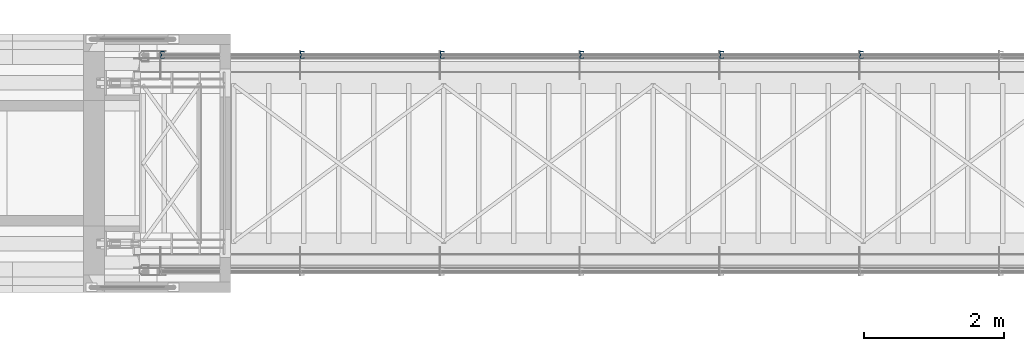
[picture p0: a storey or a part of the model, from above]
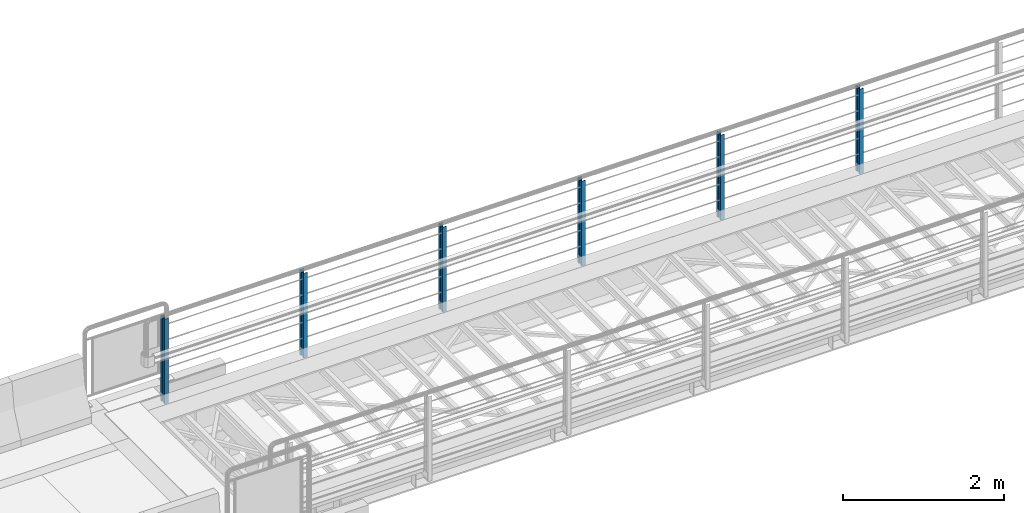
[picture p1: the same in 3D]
Properties of the parts of a building model (IFC2X3)

# File
Description: ViewDefinition[CoordinationView_V2.0, QuantityTakeOffAddOnView], ExchangeRequirement[Structural, SurfaceGeometry], Option [BaseQuantities:On], Option [GridExport:On], Option [Assemblies:Off], Option [Bolts:On], Option [Rebars:On], Option [PourObjects:Off], Option [Welds:Off], Option [SurfaceTreatments:On], Option [LocationBy:0], Option [ViewColors:Off], Option [SectionedSpine:Off], Option [PropertySets:On], Option [Export all:Off]
File name: Vippebru med betong bru.ifc
Time: 2026-04-29T15:54:14
Author: IVC\jsy
Organization: Structural Designer
Written by: IFC Parser Version: 3.13.2
Made in: Tekla Structures 2023 Service Pack 12, IFC Export Version: 4.0.0.0 Nov 4 2024

# IfcBuildingStorey, Undefined
In: Undefined
Elevation: 0 mm

# IfcBeam: CFCHS33.7*2.6 (8)
In: Undefined
Description: CFCHS33.7*2.6; Material: STEEL/S355J2+N
Pset_BeamCommon - IsExternal: no; LoadBearing: no; Reference: R-0(?)
Tekla Common - Phase: 1; Class: 3
Tekla Quantity - Volume: 0 m3; Gross footprint area: 0 m2; Area per tons: 53.2 m2; Net surface area: 0.1 m2; Height: 33.7 mm; Width: 33.7 mm
Name | Bottom elevation | Top elevation | Weight (kg) | Tekla Quantity, Length (mm) | BaseQuantities, Length (mm) | OuterSurfaceArea (m2) | NetVolume (m3) | NetWeight (kg)
4 x LKBRØYTETETTPANEL | +0.137 | +1.003 | 1.7 | 866.3 | 866.3 | 0.0918278 | 0.000210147 | 1.64965
2 x LKBRØYTETETTPANEL | +0.120 | +0.154 | 2.3 | 1175.2 | 1175.15 | 0.124566 | 0.000285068 | 2.23778
2 x LKBRØYTETETTPANEL | +0.986 | +1.020 | 2.3 | 1175.2 | 1175.15 | 0.124566 | 0.000285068 | 2.23778

# IfcBeam: CFCHS60.3*3.2 (22)
In: Undefined
Description: CFCHS60.3*3.2; Material: STEEL/S355J2+N
Pset_BeamCommon - IsExternal: no; LoadBearing: no; Reference: R-0(?)
Tekla Common - Phase: 1
Tekla Quantity - Volume: 0 m3; Gross footprint area: 0 m2; Area per tons: 41.9 m2; Height: 60.3 mm
Name | Bottom elevation | Top elevation | Class | Weight (kg) | Net surface area (m2) | Width (mm) | Tekla Quantity, Length (mm) | BaseQuantities, Length (mm) | OuterSurfaceArea (m2) | NetVolume (m3) | NetWeight (kg)
4 x LKREKKVERK | +1.094 | +1.200 | 3 | 0.5 | 0 | 3.2 | 119.4 | 119.373 | 0.0225616 | 0.0000656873 | 0.515646
4 x LKREKKVERK | +0.015 | +1.094 | 3 | 4.9 | 0.2 | 60.3 | 1078.9 | 1078.85 | 0.203903 | 0.000603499 | 4.73747
2 x LKREKKVERK | +1.140 | +1.200 | 3 | 4.6 | 0.2 | 60.3 | 1022.8 | 1022.81 | 0.193311 | 0.000572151 | 4.49139
4 x REKKVERK | +0.600 | +1.094 | 1 | 2.2 | 0.1 | 60.3 | 493.9 | 493.85 | 0.0933376 | 0.000276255 | 2.1686
4 x REKKVERK | +1.094 | +1.200 | 1 | 0.5 | 0 | 3.2 | 119.4 | 119.373 | 0.0225616 | 0.0000656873 | 0.515646
2 x BB-REKKVERK | +1.040 | +1.100 | 1 | 90.8 | 3.8 | 60.3 | 20150 | 20150 | 3.80835 | 0.0112717 | 88.4831
2 x REKKVERK | +1.140 | +1.200 | 1 | 73.3 | 3.1 | 60.3 | 16263.9 | 16263.9 | 3.07387 | 0.00909786 | 71.4182

# IfcBeam: CW100-5-10*55-10-30 (20)
In: Undefined
Description: CW100-5-10*55-10-30; Material: STEEL/S355J2+N
Tekla Common - Bottom elevation: -0.150; Phase: 1; Class: 1
Tekla Quantity - Volume: 0 m3; Gross footprint area: 0 m2; Area per tons: 52.5 m2; Height: 100 mm; Width: 55 mm
Pset_BeamCommon - IsExternal: no; LoadBearing: no; Reference: ST-0(?)
Name | Top elevation | Weight (kg) | Net surface area (m2) | Tekla Quantity, Length (mm) = BaseQuantities, Length (mm) | OuterSurfaceArea (m2) | NetVolume (m3) | NetWeight (kg)
11 x BB-STOLPE | +1.040 | 10.2 | 0.5 | 1190 | 0.533593 | 0.00129508 | 10.1664
9 x STOLPE | +1.140 | 11 | 0.6 | 1290 | 0.57825 | 0.00140391 | 11.0207

# IfcBeam: D10 (4)
In: Undefined
Description: D10; Material: STEEL/S355J2+N
Pset_BeamCommon - IsExternal: no; LoadBearing: no; Reference: R-0(?)
Tekla Common - Phase: 1; Class: 1
Tekla Quantity - Weight: 11.2 kg; Volume: 0 m3; Gross footprint area: 0 m2; Area per tons: 55.2 m2; Net surface area: 0.6 m2; Height: 10 mm; Width: 10 mm; Length: 20000 mm
BaseQuantities - Length: 20000 mm; OuterSurfaceArea: 0.612435 m2; NetVolume: 0.00141421 m3; NetWeight: 11.1016 kg
Name | Bottom elevation | Top elevation
2 x BB-REKKVERK | +0.250 | +0.260
2 x BB-REKKVERK | +0.120 | +0.130

# IfcBeam: D12 (8)
In: Undefined
Description: D12; Material: STEEL/S355J2+N
Tekla Common - Phase: 1; Class: 1
Tekla Quantity - Weight: 12.8 kg; Volume: 0 m3; Gross footprint area: 0 m2; Area per tons: 46 m2; Net surface area: 0.6 m2; Height: 12 mm; Width: 12 mm; Length: 15960 mm
Pset_BeamCommon - IsExternal: no; LoadBearing: no; Reference: R-0(?)
BaseQuantities - Length: 15960 mm; OuterSurfaceArea: 0.586536 m2; NetVolume: 0.0016251 m3; NetWeight: 12.757 kg
Name | Bottom elevation | Top elevation
2 x REKKVERK | +0.114 | +0.126
2 x REKKVERK | +0.774 | +0.786
2 x REKKVERK | +1.014 | +1.026
2 x REKKVERK | +0.354 | +0.366

# IfcBeam: D205 (2)
In: Undefined
Description: D205; Material: STEEL/S355J2+N
Tekla Common - Bottom elevation: -1.723; Top elevation: -1.517; Phase: 1; Class: 11
Tekla Quantity - Weight: 539.2 kg; Volume: 0.1 m3; Gross footprint area: 0 m2; Area per tons: 2.6 m2; Net surface area: 1.4 m2; Height: 205 mm; Width: 205 mm; Length: 2105 mm
Pset_BeamCommon - IsExternal: no; LoadBearing: no; Reference: V-0(?)
BaseQuantities - Length: 2105 mm; OuterSurfaceArea: 1.41707 m2; NetVolume: 0.0686874 m3; NetWeight: 539.196 kg

# IfcBeam: FL200*5 (2)
In: Undefined
Description: FL200*5; Material: STEEL/S355J2+N
Pset_BeamCommon - IsExternal: no; LoadBearing: no; Reference: V-0(?)
Tekla Common - Bottom elevation: -0.005; Top elevation: +0.000; Phase: 1; Class: 5
Tekla Quantity - Volume: 0 m3; Gross footprint area: 3.3 m2; Area per tons: 52.2 m2; Net surface area: 6.8 m2; Height: 200 mm; Width: 5 mm
Name | Weight (kg) | Tekla Quantity, Length (mm) = BaseQuantities, Length (mm) | OuterSurfaceArea (m2) | NetVolume (m3) | NetWeight (kg)
RIST | 129.7 | 16520.9 | 6.77556 | 0.0165209 | 129.689
RIST | 129.4 | 16480 | 6.7588 | 0.01648 | 129.368

# IfcBeam: FL50*5 (4)
In: Undefined
Description: FL50*5; Material: STEEL/S355J2+N
Pset_BeamCommon - IsExternal: no; LoadBearing: no; Reference: V-0(?)
Tekla Common - Bottom elevation: -0.055; Top elevation: -0.005; Phase: 1; Class: 3
Tekla Quantity - Weight: 32.3 kg; Volume: 0 m3; Gross footprint area: 0.1 m2; Area per tons: 56.1 m2; Net surface area: 1.8 m2; Height: 50 mm; Width: 5 mm; Length: 16480 mm
BaseQuantities - Length: 16480 mm; OuterSurfaceArea: 1.8133 m2; NetVolume: 0.00412 m3; NetWeight: 32.342 kg

# IfcBeam: HEA450 (2)
In: Undefined
Description: HEA450; Material: STEEL/S355J2+N
Pset_BeamCommon - IsExternal: no; LoadBearing: no; Reference: V-0(?)
Tekla Common - Bottom elevation: -0.440; Top elevation: +0.000; Phase: 1; Class: 11
Tekla Quantity - Weight: 2302.6 kg; Volume: 0.3 m3; Gross footprint area: 4.9 m2; Area per tons: 14.5 m2; Net surface area: 33.5 m2; Height: 440 mm; Width: 300 mm; Length: 16479.1 mm
BaseQuantities - Length: 16479.1 mm; OuterSurfaceArea: 33.1395 m2; NetVolume: 0.279172 m3; NetWeight: 2191.5 kg

# IfcBeam: IPE120 (34)
In: Undefined
Description: IPE120; Material: STEEL/S355J2+N
Pset_BeamCommon - IsExternal: no; LoadBearing: no; Reference: V-0(?)
Tekla Common - Bottom elevation: -0.165; Top elevation: -0.045; Phase: 1; Class: 11
Tekla Quantity - Weight: 23.7 kg; Volume: 0 m3; Gross footprint area: 0.1 m2; Area per tons: 45.8 m2; Net surface area: 1.1 m2; Height: 120 mm; Width: 64 mm; Length: 2288.5 mm
BaseQuantities - Length: 2288.5 mm; OuterSurfaceArea: 1.08704 m2; NetVolume: 0.0029269 m3; NetWeight: 22.9762 kg

# IfcBeam: L50*5 (14)
In: Undefined
Description: L50*5; Material: STEEL/S355J2+N
Pset_BeamCommon - IsExternal: no; LoadBearing: no; Reference: V-0(?)
Tekla Common - Bottom elevation: -0.215; Top elevation: -0.165; Phase: 1; Class: 11
Tekla Quantity - Volume: 0 m3; Area per tons: 51.5 m2; Height: 50 mm; Width: 50 mm
Name | Weight (kg) | Gross footprint area (m2) | Net surface area (m2) | Tekla Quantity, Length (mm) | BaseQuantities, Length (mm) | OuterSurfaceArea (m2) | NetVolume (m3) | NetWeight (kg)
4 x STÅLBJELKE | 5.3 | 0.1 | 0.3 | 1400 | 1400 | 0.2716 | 0.000665 | 5.22025
10 x STÅLBJELKE | 14.1 | 0.2 | 0.6 | 3744 | 3744.01 | 0.726338 | 0.0017784 | 13.9605

# IfcBeam: O120*20 (4)
In: Undefined
Description: O120*20; Material: STEEL/S355J2+N
Pset_BeamCommon - IsExternal: no; LoadBearing: no; Reference: V-0(?)
Tekla Common - Bottom elevation: -1.680; Top elevation: -1.560; Phase: 1; Class: 4
Tekla Quantity - Weight: 1.9 kg; Volume: 0 m3; Gross footprint area: 0 m2; Area per tons: 11.6 m2; Net surface area: 0 m2; Height: 120 mm; Width: 120 mm; Length: 40 mm
BaseQuantities - Length: 40 mm; OuterSurfaceArea: 0.0224341 m2; NetVolume: 0.000247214 m3; NetWeight: 1.94063 kg

# IfcBeam: O120*25 (4)
In: Undefined
Description: O120*25; Material: STEEL/S355J2+N
Tekla Common - Bottom elevation: -1.680; Top elevation: -1.560; Phase: 1; Class: 5
Tekla Quantity - Weight: 2.3 kg; Volume: 0 m3; Gross footprint area: 0 m2; Area per tons: 10.5 m2; Net surface area: 0 m2; Height: 120 mm; Width: 120 mm; Length: 40 mm
Pset_BeamCommon - IsExternal: no; LoadBearing: no; Reference: I-0(?)
BaseQuantities - Length: 40 mm; OuterSurfaceArea: 0.0242882 m2; NetVolume: 0.000293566 m3; NetWeight: 2.30449 kg

# IfcBeam: O150*30 (6)
In: Undefined
Description: O150*30; Material: STEEL/S355J2+N
Pset_BeamCommon - IsExternal: no; LoadBearing: no
Tekla Common - Bottom elevation: -0.225; Top elevation: -0.075; Phase: 1
Tekla Quantity - Volume: 0 m3; Gross footprint area: 0 m2; Net surface area: 0 m2; Height: 150 mm; Width: 150 mm
Name | Reference | Class | Weight (kg) | Area per tons (m2) | Tekla Quantity, Length (mm) = BaseQuantities, Length (mm) | OuterSurfaceArea (m2) | NetVolume (m3) | NetWeight (kg)
4 x INNFESTING | I-0(?) | 5 | 2.6 | 10.7 | 30 | 0.0280731 | 0.000335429 | 2.63312
2 x STÅLBJELKE | V-0(?) | 11 | 5.3 | 7.9 | 60 | 0.0421699 | 0.000670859 | 5.26624

# IfcColumn: CW100-5-10*55-10-30 (20)
In: Undefined
Description: CW100-5-10*55-10-30; Material: STEEL/S355J2+N
Tekla Common - Bottom elevation: -0.150; Phase: 1; Class: 1
Tekla Quantity - Volume: 0 m3; Gross footprint area: 0 m2; Area per tons: 52.5 m2; Height: 100 mm; Width: 55 mm
Pset_ColumnCommon - IsExternal: no; LoadBearing: no; Reference: ST-0(?)
Name | Top elevation | Weight (kg) | Net surface area (m2) | Tekla Quantity, Length (mm) = BaseQuantities, Length (mm) | OuterSurfaceArea (m2) | NetVolume (m3) | NetWeight (kg)
11 x BB-STOLPE | +1.040 | 10.2 | 0.5 | 1190 | 0.533593 | 0.00129508 | 10.1664
9 x STOLPE | +1.140 | 11 | 0.6 | 1290 | 0.57825 | 0.00140391 | 11.0207

# IfcPlate: PL1*830 (2)
In: Undefined
Description: PL1*830; Material: STEEL/S355J2+N
Pset_PlateCommon - IsExternal: no; LoadBearing: no; Reference: 0(?)
Tekla Common - Bottom elevation: +0.155; Top elevation: +0.985; Phase: 1; Class: 3
Tekla Quantity - Weight: 6 kg; Volume: 0 m3; Gross footprint area: 0 m2; Area per tons: 255.4 m2; Net surface area: 1.4 m2; Height: 830 mm; Width: 1 mm; Length: 920 mm
BaseQuantities - Width: 830 mm; NetArea: 1.5307 m2; GrossArea: 0.7636 m2; CrossSectionArea: 0.000001 m2; NetVolume: 0.0007636 m3; GrossVolume: 0.0007636 m3

# IfcPlate: PL10*190 (2)
In: Undefined
Description: PL10*190; Material: STEEL/S355J2+N
Pset_PlateCommon - IsExternal: no; LoadBearing: no; Reference: V-0(?)
Tekla Common - Bottom elevation: +0.000; Top elevation: +0.010; Phase: 1; Class: 5
Tekla Quantity - Weight: 11.2 kg; Volume: 0 m3; Gross footprint area: 0.1 m2; Area per tons: 27.2 m2; Net surface area: 0.3 m2; Height: 190 mm; Width: 10 mm; Length: 750 mm
BaseQuantities - Width: 190 mm; NetArea: 0.3038 m2; GrossArea: 0.1425 m2; CrossSectionArea: 0.0001 m2; NetVolume: 0.001425 m3; GrossVolume: 0.001425 m3

# IfcPlate: PL10*500, OVERGANGSPLATE
In: Undefined
Description: PL10*500; Material: STEEL/S355J2+N
Pset_PlateCommon - IsExternal: no; LoadBearing: no; Reference: V-0(?)
Tekla Common - Bottom elevation: +0.000; Top elevation: +0.010; Phase: 1; Class: 5
Tekla Quantity - Weight: 117.8 kg; Volume: 0 m3; Gross footprint area: 1.5 m2; Area per tons: 26.1 m2; Net surface area: 3.1 m2; Height: 500 mm; Width: 10 mm; Length: 3000 mm
BaseQuantities - Width: 500 mm; NetArea: 3.07 m2; GrossArea: 1.5 m2; CrossSectionArea: 0.0001 m2; NetVolume: 0.015 m3; GrossVolume: 0.015 m3

# IfcPlate: PL15*120 (4)
In: Undefined
Description: PL15*120
Pset_PlateCommon - IsExternal: no; LoadBearing: no; Reference: 0(?)
Tekla Common - Bottom elevation: +0.000; Top elevation: +0.015; Phase: 1; Class: 3
Tekla Quantity - Weight: 2.3 kg; Volume: 0 m3; Gross footprint area: 0 m2; Area per tons: 20.7 m2; Net surface area: 0 m2; Height: 120 mm; Width: 15 mm; Length: 160 mm
BaseQuantities - Width: 120 mm; NetArea: 0.0468 m2; GrossArea: 0.019201 m2; CrossSectionArea: 0.000225 m2; NetVolume: 0.000288 m3; GrossVolume: 0.000288 m3
Name | Material
2 x LKREKKVERK | STEEL/S355J2+N
2 x LKREKKVERK | STEEL/S235JR

# IfcPlate: PL155*150 (4)
In: Undefined
Description: PL155*150; Material: STEEL/S355J2+N
Tekla Common - Bottom elevation: +0.523; Top elevation: +0.678; Phase: 1; Class: 1
Tekla Quantity - Volume: 0 m3; Gross footprint area: 0 m2; Net surface area: 0.2 m2; Height: 150 mm; Width: 155 mm
Pset_PlateCommon - IsExternal: no; LoadBearing: no; Reference: 0(?)
BaseQuantities - Width: 150 mm; CrossSectionArea: 0.024025 m2
Name | Weight (kg) | Area per tons (m2) | Length (mm) | NetArea (m2) | GrossArea (m2) | NetVolume (m3) = GrossVolume (m3)
2 x FØRINGSSKINNE | 4 | 53 | 375 | 0.209772 | 0.05625 | 0.00050433
2 x FØRINGSSKINNE | 3.4 | 53.1 | 275 | 0.177772 | 0.04125 | 0.00042683

# IfcPlate: PL16270*131 (2)
In: Undefined
Description: PL16270*131; Material: STEEL/S355J2+N
Tekla Common - Bottom elevation: +0.523; Top elevation: +0.678; Phase: 1; Class: 1
Pset_PlateCommon - IsExternal: no; LoadBearing: no; Reference: R-0(?)
Tekla Quantity - Weight: 90.4 kg; Volume: 0 m3; Gross footprint area: 0 m2; Area per tons: 88.3 m2; Net surface area: 8 m2; Height: 131.4 mm; Width: 16270 mm; Length: 102.7 mm
BaseQuantities - Width: 131.445 mm; NetArea: 7.98874 m2; GrossArea: 0.0134987 m2; CrossSectionArea: 264.713 m2; NetVolume: 0.0115183 m3; GrossVolume: 0.0115183 m3

# IfcPlate: PL18*144 (4)
In: Undefined
Description: PL18*144; Material: STEEL/S355J2+N
Pset_PlateCommon - IsExternal: no; LoadBearing: no; Reference: V-0(?)
Tekla Common - Bottom elevation: -0.419; Top elevation: -0.021; Phase: 1; Class: 4
Tekla Quantity - Weight: 8.1 kg; Volume: 0 m3; Gross footprint area: 0 m2; Area per tons: 16.6 m2; Net surface area: 0.1 m2; Height: 144.3 mm; Width: 18 mm; Length: 398 mm
BaseQuantities - Width: 144.25 mm; NetArea: 0.134344 m2; GrossArea: 0.0574115 m2; CrossSectionArea: 0.000324 m2; NetVolume: 0.00103341 m3; GrossVolume: 0.00103341 m3

# IfcPlate: PL18*239 (2)
In: Undefined
Description: PL18*239; Material: STEEL/S355J2+N
Pset_PlateCommon - IsExternal: no; LoadBearing: no; Reference: V-0(?)
Tekla Common - Bottom elevation: -0.422; Top elevation: -0.183; Phase: 1; Class: 4
Tekla Quantity - Weight: 77.3 kg; Volume: 0 m3; Gross footprint area: 0 m2; Area per tons: 15.2 m2; Net surface area: 1.2 m2; Height: 239 mm; Width: 18 mm; Length: 2288.5 mm
BaseQuantities - Width: 239 mm; NetArea: 1.18489 m2; GrossArea: 0.546952 m2; CrossSectionArea: 0.000324 m2; NetVolume: 0.00984513 m3; GrossVolume: 0.00984513 m3

# IfcPlate: PL18*370 (2)
In: Undefined
Description: PL18*370; Material: STEEL/S355J2+N
Pset_PlateCommon - IsExternal: no; LoadBearing: no; Reference: V-0(?)
Tekla Common - Phase: 1; Class: 4
Tekla Quantity - Weight: 119.6 kg; Volume: 0 m3; Gross footprint area: 0.7 m2; Area per tons: 15 m2; Net surface area: 1.8 m2; Height: 370 mm; Width: 18 mm; Length: 2288.5 mm
BaseQuantities - Width: 370 mm; NetArea: 1.7892 m2; GrossArea: 0.846745 m2; CrossSectionArea: 0.000324 m2; NetVolume: 0.0152414 m3; GrossVolume: 0.0152414 m3
Name | Bottom elevation | Top elevation
PLATE | -0.183 | -0.165
PLATE | -0.440 | -0.422

# IfcPlate: PL18*466 (4)
In: Undefined
Description: PL18*466; Material: STEEL/S355J2+N
Pset_PlateCommon - IsExternal: no; LoadBearing: no; Reference: V-0(?)
Tekla Common - Bottom elevation: -1.736; Top elevation: -0.440; Phase: 1; Class: 4
Tekla Quantity - Weight: 90.7 kg; Volume: 0 m3; Gross footprint area: 0 m2; Area per tons: 15.2 m2; Net surface area: 1.4 m2; Height: 466.4 mm; Width: 18 mm; Length: 2201.5 mm
BaseQuantities - Width: 466.39 mm; NetArea: 1.37477 m2; GrossArea: 1.02674 m2; CrossSectionArea: 0.000324 m2; NetVolume: 0.0115507 m3; GrossVolume: 0.011751 m3

# IfcPlate: PL20*144 (8)
In: Undefined
Description: PL20*144; Material: STEEL/S355J2+N
Pset_PlateCommon - IsExternal: no; LoadBearing: no; Reference: V-0(?)
Tekla Common - Bottom elevation: -0.419; Top elevation: -0.021; Phase: 1; Class: 4
Tekla Quantity - Weight: 9 kg; Volume: 0 m3; Gross footprint area: 0 m2; Area per tons: 15.2 m2; Net surface area: 0.1 m2; Height: 144.3 mm; Width: 20 mm; Length: 398 mm
BaseQuantities - Width: 144.25 mm; NetArea: 0.136513 m2; GrossArea: 0.0574115 m2; CrossSectionArea: 0.0004 m2; NetVolume: 0.00114823 m3; GrossVolume: 0.00114823 m3

# IfcPlate: PL20*230 (2)
In: Undefined
Description: PL20*230; Material: STEEL/S355J2+N
Pset_PlateCommon - IsExternal: no; LoadBearing: no; Reference: I-0(?)
Tekla Common - Bottom elevation: -0.380; Top elevation: -0.150; Phase: 1; Class: 5
Tekla Quantity - Weight: 12.6 kg; Volume: 0 m3; Gross footprint area: 0 m2; Area per tons: 14.6 m2; Net surface area: 0.2 m2; Height: 230 mm; Width: 20 mm; Length: 350 mm
BaseQuantities - Width: 230 mm; NetArea: 0.1842 m2; GrossArea: 0.0805 m2; CrossSectionArea: 0.0004 m2; NetVolume: 0.00161 m3; GrossVolume: 0.00161 m3

# IfcPlate: PL20*270 (4)
In: Undefined
Description: PL20*270; Material: STEEL/S355J2+N
Tekla Common - Bottom elevation: -1.830; Top elevation: -1.560; Phase: 1; Class: 5
Tekla Quantity - Weight: 12.5 kg; Volume: 0 m3; Gross footprint area: 0 m2; Area per tons: 15 m2; Net surface area: 0.2 m2; Height: 270.3 mm; Width: 20 mm; Length: 340.2 mm
Pset_PlateCommon - IsExternal: no; LoadBearing: no; Reference: I-0(?)
BaseQuantities - Width: 270.31 mm; NetArea: 0.18825 m2; GrossArea: 0.0919571 m2; CrossSectionArea: 0.0004 m2; NetVolume: 0.00159834 m3; GrossVolume: 0.00182013 m3

# IfcPlate: PL20*300 (10)
In: Undefined
Description: PL20*300; Material: STEEL/S355J2+N
Tekla Common - Phase: 1
Tekla Quantity - Volume: 0 m3; Gross footprint area: 0 m2; Height: 300 mm; Width: 20 mm
Pset_PlateCommon - IsExternal: no; LoadBearing: no
BaseQuantities - CrossSectionArea: 0.0004 m2
Name | Bottom elevation | Top elevation | Class | Weight (kg) | Area per tons (m2) | Net surface area (m2) | Length (mm) | Reference | Width (mm) | NetArea (m2) | GrossArea (m2) | NetVolume (m3) | GrossVolume (m3)
2 x PLATE | -0.317 | -0.021 | 4 | 14.4 | 14.5 | 0.2 | 315.3 | V-0(?) | 300 | 0.209355 | 0.0945777 | 0.0018391 | 0.002028
2 x PLATE | -0.440 | -0.316 | 4 | 21.4 | 14.2 | 0.3 | 457.2 | V-0(?) | 300 | 0.303273 | 0.137163 | 0.00272915 | 0.002748
2 x INNFESTING | -1.830 | -1.530 | 5 | 16.5 | 14.2 | 0.2 | 350 | I-0(?) | 300 | 0.236 | 0.105 | 0.0021 | 0.0021
PLATE | -1.518 | -0.440 | 4 | 68.4 | 13.8 | 0.9 | 1461.5 | V-0(?) | 300.006 | 0.943633 | 0.438464 | 0.0087138 | 0.00881991
2 x PLATE | -1.666 | -0.440 | 4 | 94.8 | 13.8 | 1.2 | 2024.9 | V-0(?) | 300 | 1.30345 | 0.607476 | 0.0120707 | 0.0121495
PLATE | -1.518 | -0.440 | 4 | 68 | 13.8 | 0.9 | 1443.4 | V-0(?) | 300.006 | 0.935742 | 0.433017 | 0.00866009 | 0.00866009

# IfcPlate: PL20*350 (4)
In: Undefined
Description: PL20*350; Material: STEEL/S355J2+N
Pset_PlateCommon - IsExternal: no; LoadBearing: no; Reference: I-0(?)
Tekla Common - Phase: 1; Class: 5
Tekla Quantity - Weight: 27.5 kg; Volume: 0 m3; Gross footprint area: 0.2 m2; Area per tons: 14 m2; Net surface area: 0.3 m2; Height: 350 mm; Width: 20 mm; Length: 500 mm
BaseQuantities - Width: 350 mm; NetArea: 0.384 m2; GrossArea: 0.175 m2; CrossSectionArea: 0.0004 m2; NetVolume: 0.0035 m3; GrossVolume: 0.0035 m3
Name | Bottom elevation | Top elevation
2 x INNFESTING | -1.850 | -1.830
2 x INNFESTING | -0.400 | -0.380

# IfcPlate: PL20*355 (4)
In: Undefined
Description: PL20*355; Material: STEEL/S355J2+N
Pset_PlateCommon - IsExternal: no; LoadBearing: no; Reference: I-0(?)
Tekla Common - Bottom elevation: -0.380; Top elevation: -0.025; Phase: 1; Class: 5
Tekla Quantity - Weight: 18.2 kg; Volume: 0 m3; Gross footprint area: 0 m2; Area per tons: 15 m2; Net surface area: 0.3 m2; Height: 354.8 mm; Width: 20 mm; Length: 480 mm
BaseQuantities - Width: 354.777 mm; NetArea: 0.270588 m2; GrossArea: 0.170293 m2; CrossSectionArea: 0.0004 m2; NetVolume: 0.0023211 m3; GrossVolume: 0.0026705 m3

# IfcPlate: PL20100*131 (2)
In: Undefined
Description: PL20100*131; Material: STEEL/S355J2+N
Tekla Common - Bottom elevation: +0.523; Top elevation: +0.678; Phase: 1; Class: 1
Tekla Quantity - Weight: 111.7 kg; Volume: 0 m3; Gross footprint area: 0 m2; Area per tons: 88.3 m2; Net surface area: 9.9 m2; Height: 131.4 mm; Width: 20100 mm; Length: 102.7 mm
Pset_PlateCommon - IsExternal: no; LoadBearing: no; Reference: R-0(?)
BaseQuantities - Width: 131.445 mm; NetArea: 9.86897 m2; GrossArea: 0.0134987 m2; CrossSectionArea: 404.01 m2; NetVolume: 0.0142298 m3; GrossVolume: 0.0142298 m3

# IfcPlate: PL40*291 (2)
In: Undefined
Description: PL40*291; Material: STEEL/S355J2+N
Pset_PlateCommon - IsExternal: no; LoadBearing: no; Reference: I-0(?)
Tekla Common - Bottom elevation: -0.312; Top elevation: -0.021; Phase: 1; Class: 11
Tekla Quantity - Weight: 26.2 kg; Volume: 0 m3; Gross footprint area: 0 m2; Area per tons: 8.2 m2; Net surface area: 0.2 m2; Height: 291 mm; Width: 40 mm; Length: 393.4 mm
BaseQuantities - Width: 291.008 mm; NetArea: 0.215701 m2; GrossArea: 0.114473 m2; CrossSectionArea: 0.0016 m2; NetVolume: 0.00334393 m3; GrossVolume: 0.00334393 m3

# IfcPlate: PL45*2000, RIST
In: Undefined
Description: PL45*2000; Material: STEEL/S355J2+N
Pset_PlateCommon - IsExternal: no; LoadBearing: no; Reference: I-0(?)
Tekla Common - Bottom elevation: -0.045; Top elevation: +0.000; Phase: 1; Class: 5
Tekla Quantity - Weight: 11643.1 kg; Volume: 1.5 m3; Gross footprint area: 33 m2; Area per tons: 5.8 m2; Net surface area: 67.6 m2; Height: 2000 mm; Width: 45 mm; Length: 16480 mm
BaseQuantities - Width: 2000 mm; NetArea: 67.5832 m2; GrossArea: 32.96 m2; CrossSectionArea: 0.002025 m2; NetVolume: 1.4832 m3; GrossVolume: 1.4832 m3

# IfcPlate: PL5*362, PLATE
In: Undefined
Description: PL5*362; Material: STEEL/S355J2+N
Pset_PlateCommon - IsExternal: no; LoadBearing: no; Reference: V-0(?)
Tekla Common - Bottom elevation: -0.383; Top elevation: -0.021; Phase: 1; Class: 4
Tekla Quantity - Weight: 2.6 kg; Volume: 0 m3; Gross footprint area: 0 m2; Area per tons: 53.9 m2; Net surface area: 0.1 m2; Height: 362 mm; Width: 5 mm; Length: 400 mm
BaseQuantities - Width: 362 mm; NetArea: 0.14002 m2; GrossArea: 0.1448 m2; CrossSectionArea: 0.000025 m2; NetVolume: 0.000331 m3; GrossVolume: 0.000331 m3

# IfcPlate: PL5*363, PLATE
In: Undefined
Description: PL5*363; Material: STEEL/S355J2+N
Pset_PlateCommon - IsExternal: no; LoadBearing: no; Reference: V-0(?)
Tekla Common - Bottom elevation: -0.384; Top elevation: -0.021; Phase: 1; Class: 4
Tekla Quantity - Weight: 2.6 kg; Volume: 0 m3; Gross footprint area: 0 m2; Area per tons: 53.9 m2; Net surface area: 0.1 m2; Height: 363.2 mm; Width: 5 mm; Length: 400 mm
BaseQuantities - Width: 363.153 mm; NetArea: 0.140152 m2; GrossArea: 0.145261 m2; CrossSectionArea: 0.000025 m2; NetVolume: 0.000331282 m3; GrossVolume: 0.000349 m3

# IfcPlate: PL5*398 (16)
In: Undefined
Description: PL5*398; Material: STEEL/S355J2+N
Pset_PlateCommon - IsExternal: no; LoadBearing: no; Reference: V-0(?)
Tekla Common - Bottom elevation: -0.419; Top elevation: -0.021; Phase: 1; Class: 4
Tekla Quantity - Weight: 2.7 kg; Volume: 0 m3; Gross footprint area: 0 m2; Area per tons: 53.9 m2; Net surface area: 0.1 m2; Height: 398 mm; Width: 5 mm; Length: 400 mm
BaseQuantities - Width: 398 mm; NetArea: 0.14758 m2; GrossArea: 0.1592 m2; CrossSectionArea: 0.000025 m2; NetVolume: 0.000349 m3; GrossVolume: 0.000349 m3

# IfcPlate: PL50*1200, LUKE
In: Undefined
Description: PL50*1200; Material: STEEL/S355J2+N
Pset_PlateCommon - IsExternal: no; LoadBearing: no; Reference: V-0(?)
Tekla Common - Bottom elevation: -0.050; Top elevation: +0.000; Phase: 1; Class: 4
Tekla Quantity - Weight: 706.5 kg; Volume: 0.1 m3; Gross footprint area: 1.7 m2; Area per tons: 5.5 m2; Net surface area: 3.9 m2; Height: 1200 mm; Width: 50 mm; Length: 1500 mm
BaseQuantities - Width: 1200 mm; NetArea: 3.87 m2; GrossArea: 1.8 m2; CrossSectionArea: 0.0025 m2; NetVolume: 0.09 m3; GrossVolume: 0.09 m3

# IfcPlate: PL50*700 (2)
In: Undefined
Description: PL50*700; Material: STEEL/S355J2+N
Pset_PlateCommon - IsExternal: no; LoadBearing: no; Reference: V-0(?)
Tekla Common - Bottom elevation: -0.050; Top elevation: +0.000; Phase: 1; Class: 4
Tekla Quantity - Weight: 631.9 kg; Volume: 0.1 m3; Gross footprint area: 1.6 m2; Area per tons: 5.6 m2; Net surface area: 3.5 m2; Height: 700 mm; Width: 50 mm; Length: 2300 mm
BaseQuantities - Width: 700 mm; NetArea: 3.52 m2; GrossArea: 1.61 m2; CrossSectionArea: 0.0025 m2; NetVolume: 0.0805 m3; GrossVolume: 0.0805 m3

# IfcPlate: PL74*177 (2)
In: Undefined
Description: PL74*177; Material: STEEL/S355J2+N
Pset_PlateCommon - IsExternal: no; LoadBearing: no; Reference: V-0(?)
Tekla Common - Bottom elevation: -1.722; Top elevation: -1.517; Phase: 1; Class: 11
Tekla Quantity - Weight: 15.5 kg; Volume: 0 m3; Gross footprint area: 0 m2; Area per tons: 7.9 m2; Net surface area: 0.1 m2; Height: 177 mm; Width: 74 mm; Length: 205 mm
BaseQuantities - Width: 177 mm; NetArea: 0.121902 m2; GrossArea: 0.036285 m2; CrossSectionArea: 0.005476 m2; NetVolume: 0.00197536 m3; GrossVolume: 0.00233783 m3

# IfcPlate: PL74*205 (2)
In: Undefined
Description: PL74*205; Material: STEEL/S355J2+N
Pset_PlateCommon - IsExternal: no; LoadBearing: no; Reference: V-0(?)
Tekla Common - Bottom elevation: -1.722; Top elevation: -1.517; Phase: 1; Class: 11
Tekla Quantity - Weight: 20.4 kg; Volume: 0 m3; Gross footprint area: 0 m2; Area per tons: 7.1 m2; Net surface area: 0.1 m2; Height: 205 mm; Width: 74 mm; Length: 218 mm
BaseQuantities - Width: 205 mm; NetArea: 0.14478 m2; GrossArea: 0.04469 m2; CrossSectionArea: 0.005476 m2; NetVolume: 0.00259733 m3; GrossVolume: 0.0029598 m3

# IfcSlab: 1020*860 (2)
In: Undefined
Description: 1020*860; Material: CONCRETE/B35
Tekla Common - Bottom elevation: -0.000; Top elevation: +0.860; Phase: 1; Class: 1
Pset_SlabCommon - IsExternal: no; Compartmentation: no; LoadBearing: no; Reference: CP_PD-1-0(?)
Tekla Quantity - Weight: 572.8 kg; Volume: 0.2 m3; Gross footprint area: 0.1 m2; Area per tons: 5 m2; Net surface area: 2.8 m2; Height: 860 mm; Width: 1020 mm; Length: 440 mm
BaseQuantities - Width: 1020 mm; NetVolume: 0.23868 m3; NetArea: 0.1224 m2; NetWeight: 572.833 kg

# IfcSlab: 120*3700, PLASSTØPTDEKKE
In: Undefined
Description: 120*3700; Material: CONCRETE/B35
Pset_SlabCommon - IsExternal: no; Compartmentation: no; LoadBearing: no; Reference: CP_PD-1-0(?)
Tekla Common - Bottom elevation: -0.120; Top elevation: +0.000; Phase: 1; Class: 1
Tekla Quantity - Weight: 21471.8 kg; Volume: 8.9 m3; Gross footprint area: 74.6 m2; Area per tons: 7.1 m2; Net surface area: 154.8 m2; Height: 3700 mm; Width: 120 mm; Length: 20150 mm
BaseQuantities - Width: 120 mm; NetVolume: 8.9466 m3; NetArea: 74.555 m2; NetWeight: 21471.8 kg

# IfcSlab: 1360*860 (6)
In: Undefined
Description: 1360*860; Material: CONCRETE/B35
Tekla Common - Bottom elevation: -0.000; Top elevation: +0.860; Phase: 1; Class: 1
Tekla Quantity - Weight: 763.8 kg; Volume: 0.3 m3; Gross footprint area: 0.2 m2; Area per tons: 4.8 m2; Net surface area: 3.6 m2; Height: 860 mm; Width: 1360 mm; Length: 440 mm
Pset_SlabCommon - IsExternal: no; Compartmentation: no; LoadBearing: no; Reference: CP_PD-1-0(?)
BaseQuantities - Width: 1360 mm; NetVolume: 0.31824 m3; NetArea: 0.1632 m2; NetWeight: 763.777 kg

# IfcSlab: 200*1100, PLASSTØPTDEKKE
In: Undefined
Description: 200*1100; Material: CONCRETE/B35
Pset_SlabCommon - IsExternal: no; Compartmentation: no; LoadBearing: no; Reference: CP_PD-1-0(?)
Tekla Common - Bottom elevation: -0.200; Top elevation: +0.000; Phase: 1; Class: 1
Tekla Quantity - Weight: 792 kg; Volume: 0.3 m3; Gross footprint area: 1.7 m2; Area per tons: 5.5 m2; Net surface area: 4.3 m2; Height: 1100 mm; Width: 200 mm; Length: 1500 mm
BaseQuantities - Width: 200 mm; NetVolume: 0.33 m3; NetArea: 1.65 m2; NetWeight: 792 kg

# IfcSlab: 200*2500, PLASSTØPTDEKKE
In: Undefined
Description: 200*2500; Material: CONCRETE/B35
Pset_SlabCommon - IsExternal: no; Compartmentation: no; LoadBearing: no; Reference: CP_PD-1-0(?)
Tekla Common - Bottom elevation: -0.200; Top elevation: +0.000; Phase: 1; Class: 1
Tekla Quantity - Weight: 3840 kg; Volume: 1.6 m3; Gross footprint area: 8 m2; Area per tons: 4.8 m2; Net surface area: 18.3 m2; Height: 2500 mm; Width: 200 mm; Length: 3200 mm
BaseQuantities - Width: 200 mm; NetVolume: 1.6 m3; NetArea: 8 m2; NetWeight: 3840 kg

# IfcSlab: 250*3700, PLASSTØPTDEKKE
In: Undefined
Description: 250*3700; Material: CONCRETE/B35
Pset_SlabCommon - IsExternal: no; Compartmentation: no; LoadBearing: no; Reference: CP_PD-1-0(?)
Tekla Common - Bottom elevation: -2.100; Top elevation: -1.850; Phase: 1; Class: 1
Tekla Quantity - Weight: 15984 kg; Volume: 6.7 m3; Gross footprint area: 26.6 m2; Area per tons: 3.7 m2; Net surface area: 58.7 m2; Height: 3700 mm; Width: 250 mm; Length: 7200 mm
BaseQuantities - Width: 250 mm; NetVolume: 6.66 m3; NetArea: 26.64 m2; NetWeight: 15984 kg

# IfcSlab: 250*750, PLASSTØPTDEKKE
In: Undefined
Description: 250*750; Material: CONCRETE/B35
Pset_SlabCommon - IsExternal: no; Compartmentation: no; LoadBearing: no; Reference: CP_PD-1-0(?)
Tekla Common - Bottom elevation: -2.350; Top elevation: -2.100; Phase: 1; Class: 1
Tekla Quantity - Weight: 1665 kg; Volume: 0.8 m3; Gross footprint area: 2.8 m2; Area per tons: 4.7 m2; Net surface area: 7.8 m2; Height: 750 mm; Width: 250 mm; Length: 3700 mm
BaseQuantities - Width: 250 mm; NetVolume: 0.69375 m3; NetArea: 2.775 m2; NetWeight: 1665 kg

# IfcSlab: 800*3700, PLASSTØPTDEKKE
In: Undefined
Description: 800*3700; Material: CONCRETE/B35
Pset_SlabCommon - IsExternal: no; Compartmentation: no; LoadBearing: no; Reference: CP_PD-1-0(?)
Tekla Common - Bottom elevation: -0.920; Top elevation: -0.120; Phase: 1; Class: 1
Tekla Quantity - Weight: 142080 kg; Volume: 59.2 m3; Gross footprint area: 74 m2; Area per tons: 1.3 m2; Net surface area: 185.9 m2; Height: 3700 mm; Width: 800 mm; Length: 20000 mm
BaseQuantities - Width: 800 mm; NetVolume: 59.2 m3; NetArea: 74 m2; NetWeight: 142080 kg

# IfcWall: 1200*250 (2)
In: Undefined
Description: 1200*250; Material: CONCRETE/B35
Pset_WallCommon - IsExternal: no; Compartmentation: no; LoadBearing: no; Reference: CP_PV-1-0(?)
Tekla Common - Bottom elevation: -3.300; Top elevation: -2.100; Phase: 1; Class: 1
Tekla Quantity - Weight: 2016 kg; Volume: 0.8 m3; Gross footprint area: 0.7 m2; Area per tons: 4.3 m2; Net surface area: 8.7 m2; Height: 1200 mm; Width: 250 mm; Length: 2800 mm
BaseQuantities - Length: 2800 mm; OuterSurfaceArea: 8.72 m2; NetVolume: 0.84 m3; NetWeight: 2016 kg

# IfcWall: 1200*300, PLASSTØPTVEGG
In: Undefined
Description: 1200*300; Material: CONCRETE/B35
Pset_WallCommon - IsExternal: no; Compartmentation: no; LoadBearing: no; Reference: CP_PV-1-0(?)
Tekla Common - Bottom elevation: -3.300; Top elevation: -2.100; Phase: 1; Class: 1
Tekla Quantity - Weight: 2764.8 kg; Volume: 1.2 m3; Gross footprint area: 1 m2; Area per tons: 3.7 m2; Net surface area: 10.3 m2; Height: 1200 mm; Width: 300 mm; Length: 3200 mm
BaseQuantities - Length: 3200 mm; OuterSurfaceArea: 10.32 m2; NetVolume: 1.152 m3; NetWeight: 2764.8 kg

# IfcWall: 1300*150 (3)
In: Undefined
Description: 1300*150; Material: CONCRETE/B35
Pset_WallCommon - IsExternal: no; Compartmentation: no; LoadBearing: no; Reference: CP_PV-1-0(?)
Tekla Common - Bottom elevation: -1.850; Top elevation: -0.550; Phase: 1; Class: 1
Tekla Quantity - Height: 1300 mm; Width: 150 mm
Name | Weight (kg) = NetWeight (kg) | Volume (m3) | Gross footprint area (m2) | Area per tons (m2) | Net surface area (m2) | Tekla Quantity, Length (mm) = BaseQuantities, Length (mm) | OuterSurfaceArea (m2) | NetVolume (m3)
PLASSTØPTVEGG | 889.2 | 0.3 | 0.4 | 6.6 | 5.9 | 1900 | 5.9 | 0.3705
2 x PLASSTØPTVEGG | 163.8 | 0.1 | 0.1 | 8.6 | 1.4 | 350 | 1.405 | 0.06825

# IfcWall: 1850*150 (4)
In: Undefined
Description: 1850*150; Material: CONCRETE/B35
Pset_WallCommon - IsExternal: no; Compartmentation: no; LoadBearing: no; Reference: CP_PV-1-0(?)
Tekla Common - Bottom elevation: -1.850; Top elevation: +0.000; Phase: 1; Class: 1
Tekla Quantity - Gross footprint area: 0.4 m2; Height: 1850 mm; Width: 150 mm
Name | Weight (kg) = NetWeight (kg) | Volume (m3) | Area per tons (m2) | Net surface area (m2) | Tekla Quantity, Length (mm) = BaseQuantities, Length (mm) | OuterSurfaceArea (m2) | NetVolume (m3)
2 x PLASSTØPTVEGG | 1531.8 | 0.6 | 6.3 | 9.9 | 2300 | 9.755 | 0.63825
2 x PLASSTØPTVEGG | 1198.8 | 0.5 | 6.5 | 7.8 | 1800 | 7.755 | 0.4995

# IfcWall: 1850*250 (4)
In: Undefined
Description: 1850*250; Material: CONCRETE/B35
Pset_WallCommon - IsExternal: no; Compartmentation: no; LoadBearing: no; Reference: CP_PV-1-0(?)
Tekla Common - Bottom elevation: -1.850; Top elevation: +0.000; Phase: 1; Class: 1
Tekla Quantity - Volume: 1.2 m3; Gross footprint area: 0.7 m2; Area per tons: 4.1 m2; Height: 1850 mm; Width: 250 mm
Name | Weight (kg) = NetWeight (kg) | Net surface area (m2) | Tekla Quantity, Length (mm) = BaseQuantities, Length (mm) | OuterSurfaceArea (m2) | NetVolume (m3)
2 x PLASSTØPTVEGG | 2886 | 11.8 | 2600 | 11.845 | 1.2025
2 x PLASSTØPTVEGG | 3108 | 12.7 | 2800 | 12.685 | 1.295

# IfcWall: 1850*300 (2)
In: Undefined
Description: 1850*300; Material: CONCRETE/B35
Pset_WallCommon - IsExternal: no; Compartmentation: no; LoadBearing: no; Reference: CP_PV-1-0(?)
Tekla Common - Bottom elevation: -1.850; Top elevation: +0.000; Phase: 1; Class: 1
Tekla Quantity - Height: 1850 mm; Width: 300 mm
Name | Weight (kg) = NetWeight (kg) | Volume (m3) | Gross footprint area (m2) | Area per tons (m2) | Net surface area (m2) | Tekla Quantity, Length (mm) = BaseQuantities, Length (mm) | OuterSurfaceArea (m2) | NetVolume (m3)
PLASSTØPTVEGG | 2397.6 | 1 | 0.4 | 3.7 | 8.9 | 1800 | 8.85 | 0.999
PLASSTØPTVEGG | 4262.4 | 1.8 | 1 | 3.5 | 14.9 | 3200 | 14.87 | 1.776

# IfcWall: 380*3700, PLASSTØPTVEGG
In: Undefined
Description: 380*3700; Material: CONCRETE/B35
Pset_WallCommon - IsExternal: no; Compartmentation: no; LoadBearing: no; Reference: CP_PV-1-0(?)
Tekla Common - Bottom elevation: -0.500; Top elevation: -0.120; Phase: 1; Class: 1
Tekla Quantity - Weight: 506.2 kg; Volume: 0.2 m3; Gross footprint area: 0.7 m2; Area per tons: 7.9 m2; Net surface area: 3.9 m2; Height: 380 mm; Width: 3700 mm; Length: 150 mm
BaseQuantities - Length: 150 mm; OuterSurfaceArea: 4.036 m2; NetVolume: 0.2109 m3; NetWeight: 506.16 kg

# IfcWall: 425*3700, PLASSTØPTVEGG
In: Undefined
Description: 425*3700; Material: CONCRETE/B35
Pset_WallCommon - IsExternal: no; Compartmentation: no; LoadBearing: no; Reference: CP_PV-1-0(?)
Tekla Common - Bottom elevation: -0.920; Top elevation: -0.495; Phase: 1; Class: 1
Tekla Quantity - Weight: 1132.2 kg; Volume: 0.5 m3; Gross footprint area: 1.1 m2; Area per tons: 5 m2; Net surface area: 5.6 m2; Height: 425 mm; Width: 3700 mm; Length: 300 mm
BaseQuantities - Length: 300 mm; OuterSurfaceArea: 5.62 m2; NetVolume: 0.47175 m3; NetWeight: 1132.2 kg

# IfcWall: 500*950 (2)
In: Undefined
Description: 500*950; Material: CONCRETE/B35
Pset_WallCommon - IsExternal: no; Compartmentation: no; LoadBearing: no; Reference: CP_PV-1-0(?)
Tekla Common - Bottom elevation: -0.900; Top elevation: -0.400; Phase: 1; Class: 1
Tekla Quantity - Weight: 570 kg; Volume: 0.2 m3; Gross footprint area: 0.4 m2; Area per tons: 4.3 m2; Net surface area: 2.4 m2; Height: 500 mm; Width: 950 mm; Length: 500 mm
BaseQuantities - Length: 500 mm; OuterSurfaceArea: 2.4 m2; NetVolume: 0.2375 m3; NetWeight: 570 kg

# IfcWall: 700*150 (2)
In: Undefined
Description: 700*150; Material: CONCRETE/B35
Pset_WallCommon - IsExternal: no; Compartmentation: no; LoadBearing: no; Reference: CP_PV-1-0(?)
Tekla Common - Bottom elevation: -1.850; Top elevation: -1.150; Phase: 1; Class: 1
Tekla Quantity - Weight: 100.8 kg; Volume: 0 m3; Gross footprint area: 0.1 m2; Area per tons: 8.8 m2; Net surface area: 0.9 m2; Height: 700 mm; Width: 150 mm; Length: 400 mm
BaseQuantities - Length: 400 mm; OuterSurfaceArea: 0.89 m2; NetVolume: 0.042 m3; NetWeight: 100.8 kg

# IfcWall: 750*4100, PLASSTØPTVEGG
In: Undefined
Description: 750*4100; Material: CONCRETE/B35
Pset_WallCommon - IsExternal: no; Compartmentation: no; LoadBearing: no; Reference: CP_PV-1-0(?)
Tekla Common - Bottom elevation: -1.670; Top elevation: -0.920; Phase: 1; Class: 1
Tekla Quantity - Weight: 5535 kg; Volume: 2.3 m3; Gross footprint area: 3.1 m2; Area per tons: 2.4 m2; Net surface area: 13.4 m2; Height: 750 mm; Width: 4100 mm; Length: 750 mm
BaseQuantities - Length: 750 mm; OuterSurfaceArea: 13.425 m2; NetVolume: 2.30625 m3; NetWeight: 5535 kg

# IfcWall: 800*200 (2)
In: Undefined
Description: 800*200; Material: CONCRETE/B35
Pset_WallCommon - IsExternal: no; Compartmentation: no; LoadBearing: no; Reference: CP_PV-1-0(?)
Tekla Common - Bottom elevation: -0.921; Top elevation: -0.121; Phase: 1; Class: 1
Tekla Quantity - Weight: 288 kg; Volume: 0.1 m3; Gross footprint area: 0.2 m2; Area per tons: 6.3 m2; Net surface area: 1.8 m2; Height: 800 mm; Width: 200 mm; Length: 750 mm
BaseQuantities - Length: 750 mm; OuterSurfaceArea: 1.82 m2; NetVolume: 0.12 m3; NetWeight: 288 kg

# IfcWall: 900*300 (2)
In: Undefined
Description: 900*300; Material: CONCRETE/B35
Pset_WallCommon - IsExternal: no; Compartmentation: no; LoadBearing: no; Reference: CP_PV-1-0(?)
Tekla Common - Bottom elevation: -0.900; Top elevation: +0.000; Phase: 1; Class: 1
Tekla Quantity - Weight: 453.6 kg; Volume: 0.2 m3; Gross footprint area: 0.2 m2; Area per tons: 4.8 m2; Net surface area: 2.2 m2; Height: 900 mm; Width: 300 mm; Length: 700 mm
BaseQuantities - Length: 700 mm; OuterSurfaceArea: 2.22 m2; NetVolume: 0.189 m3; NetWeight: 453.6 kg

# IfcWall: 950*100 (2)
In: Undefined
Description: 950*100; Material: CONCRETE/B35
Pset_WallCommon - IsExternal: no; Compartmentation: no; LoadBearing: no; Reference: CP_PV-1-0(?)
Tekla Common - Bottom elevation: -1.850; Top elevation: -0.900; Phase: 1; Class: 1
Tekla Quantity - Weight: 114 kg; Volume: 0 m3; Gross footprint area: 0.1 m2; Area per tons: 10.9 m2; Net surface area: 1.2 m2; Height: 950 mm; Width: 100 mm; Length: 500 mm
BaseQuantities - Length: 500 mm; OuterSurfaceArea: 1.24 m2; NetVolume: 0.0475 m3; NetWeight: 114 kg

# IfcWall: 950*150 (2)
In: Undefined
Description: 950*150; Material: CONCRETE/B35
Pset_WallCommon - IsExternal: no; Compartmentation: no; LoadBearing: no; Reference: CP_PV-1-0(?)
Tekla Common - Bottom elevation: -1.850; Top elevation: -0.900; Phase: 1; Class: 1
Tekla Quantity - Weight: 171 kg; Volume: 0.1 m3; Gross footprint area: 0.1 m2; Area per tons: 8.1 m2; Net surface area: 1.4 m2; Height: 950 mm; Width: 150 mm; Length: 500 mm
BaseQuantities - Length: 500 mm; OuterSurfaceArea: 1.385 m2; NetVolume: 0.07125 m3; NetWeight: 171 kg

# IfcWall: D750 (4)
In: Undefined
Description: D750; Material: CONCRETE/B35
Tekla Common - Phase: 1; Class: 1
Tekla Quantity - Weight: 1955.9 kg; Volume: 0.8 m3; Gross footprint area: 0.4 m2; Area per tons: 2.7 m2; Net surface area: 5.2 m2; Height: 750 mm; Width: 750 mm; Length: 1850 mm
Pset_WallCommon - IsExternal: no; Compartmentation: no; LoadBearing: no; Reference: CP_PV-1-0(?)
BaseQuantities - Length: 1850 mm; OuterSurfaceArea: 5.2369 m2; NetVolume: 0.814973 m3; NetWeight: 1955.93 kg
Name | Bottom elevation | Top elevation
2 x PLASSTØPTVEGG | -4.200 | -2.350
2 x PLASSTØPTVEGG | -3.520 | -1.670
